VERSION 5.7 ;
  NOWIREEXTENSIONATPIN ON ;
  DIVIDERCHAR "/" ;
  BUSBITCHARS "[]" ;
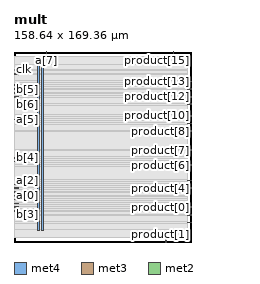
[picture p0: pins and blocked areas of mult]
MACRO mult
  CLASS BLOCK ;
  FOREIGN mult ;
  ORIGIN 0.000 0.000 ;
  SIZE 158.640 BY 169.360 ;
  PIN VGND
    DIRECTION INOUT ;
    USE GROUND ;
    PORT
      LAYER met4 ;
        RECT 24.340 10.640 25.940 158.000 ;
    END
  END VGND
  PIN VPWR
    DIRECTION INOUT ;
    USE POWER ;
    PORT
      LAYER met4 ;
        RECT 21.040 10.640 22.640 158.000 ;
    END
  END VPWR
  PIN a[0]
    DIRECTION INPUT ;
    USE SIGNAL ;
    ANTENNAGATEAREA 0.126000 ;
    PORT
      LAYER met3 ;
        RECT 0.000 40.840 4.000 41.440 ;
    END
  END a[0]
  PIN a[1]
    DIRECTION INPUT ;
    USE SIGNAL ;
    ANTENNAGATEAREA 0.126000 ;
    PORT
      LAYER met3 ;
        RECT 0.000 34.040 4.000 34.640 ;
    END
  END a[1]
  PIN a[2]
    DIRECTION INPUT ;
    USE SIGNAL ;
    ANTENNAGATEAREA 0.126000 ;
    PORT
      LAYER met3 ;
        RECT 0.000 47.640 4.000 48.240 ;
    END
  END a[2]
  PIN a[3]
    DIRECTION INPUT ;
    USE SIGNAL ;
    ANTENNAGATEAREA 0.126000 ;
    PORT
      LAYER met3 ;
        RECT 0.000 51.040 4.000 51.640 ;
    END
  END a[3]
  PIN a[4]
    DIRECTION INPUT ;
    USE SIGNAL ;
    ANTENNAGATEAREA 0.126000 ;
    PORT
      LAYER met3 ;
        RECT 0.000 71.440 4.000 72.040 ;
    END
  END a[4]
  PIN a[5]
    DIRECTION INPUT ;
    USE SIGNAL ;
    ANTENNAGATEAREA 0.126000 ;
    PORT
      LAYER met3 ;
        RECT 0.000 108.840 4.000 109.440 ;
    END
  END a[5]
  PIN a[6]
    DIRECTION INPUT ;
    USE SIGNAL ;
    ANTENNAGATEAREA 0.126000 ;
    PORT
      LAYER met3 ;
        RECT 0.000 132.640 4.000 133.240 ;
    END
  END a[6]
  PIN a[7]
    DIRECTION INPUT ;
    USE SIGNAL ;
    ANTENNAGATEAREA 0.126000 ;
    PORT
      LAYER met2 ;
        RECT 29.070 165.360 29.350 169.360 ;
    END
  END a[7]
  PIN b[0]
    DIRECTION INPUT ;
    USE SIGNAL ;
    ANTENNAGATEAREA 0.126000 ;
    PORT
      LAYER met3 ;
        RECT 0.000 37.440 4.000 38.040 ;
    END
  END b[0]
  PIN b[1]
    DIRECTION INPUT ;
    USE SIGNAL ;
    ANTENNAGATEAREA 0.126000 ;
    PORT
      LAYER met3 ;
        RECT 0.000 27.240 4.000 27.840 ;
    END
  END b[1]
  PIN b[2]
    DIRECTION INPUT ;
    USE SIGNAL ;
    ANTENNAGATEAREA 0.126000 ;
    PORT
      LAYER met3 ;
        RECT 0.000 44.240 4.000 44.840 ;
    END
  END b[2]
  PIN b[3]
    DIRECTION INPUT ;
    USE SIGNAL ;
    ANTENNAGATEAREA 0.126000 ;
    PORT
      LAYER met3 ;
        RECT 0.000 30.640 4.000 31.240 ;
    END
  END b[3]
  PIN b[4]
    DIRECTION INPUT ;
    USE SIGNAL ;
    ANTENNAGATEAREA 0.126000 ;
    PORT
      LAYER met3 ;
        RECT 0.000 74.840 4.000 75.440 ;
    END
  END b[4]
  PIN b[5]
    DIRECTION INPUT ;
    USE SIGNAL ;
    ANTENNAGATEAREA 0.126000 ;
    PORT
      LAYER met3 ;
        RECT 0.000 136.040 4.000 136.640 ;
    END
  END b[5]
  PIN b[6]
    DIRECTION INPUT ;
    USE SIGNAL ;
    ANTENNAGATEAREA 0.126000 ;
    PORT
      LAYER met3 ;
        RECT 0.000 129.240 4.000 129.840 ;
    END
  END b[6]
  PIN b[7]
    DIRECTION INPUT ;
    USE SIGNAL ;
    ANTENNAGATEAREA 0.126000 ;
    PORT
      LAYER met3 ;
        RECT 0.000 139.440 4.000 140.040 ;
    END
  END b[7]
  PIN clk
    DIRECTION INPUT ;
    USE SIGNAL ;
    ANTENNAGATEAREA 0.852000 ;
    PORT
      LAYER met3 ;
        RECT 0.000 153.040 4.000 153.640 ;
    END
  END clk
  PIN product[0]
    DIRECTION OUTPUT ;
    USE SIGNAL ;
    ANTENNADIFFAREA 0.445500 ;
    PORT
      LAYER met3 ;
        RECT 154.640 30.640 158.640 31.240 ;
    END
  END product[0]
  PIN product[10]
    DIRECTION OUTPUT ;
    USE SIGNAL ;
    ANTENNADIFFAREA 0.445500 ;
    PORT
      LAYER met3 ;
        RECT 154.640 112.240 158.640 112.840 ;
    END
  END product[10]
  PIN product[11]
    DIRECTION OUTPUT ;
    USE SIGNAL ;
    ANTENNADIFFAREA 0.445500 ;
    PORT
      LAYER met3 ;
        RECT 154.640 122.440 158.640 123.040 ;
    END
  END product[11]
  PIN product[12]
    DIRECTION OUTPUT ;
    USE SIGNAL ;
    ANTENNADIFFAREA 0.445500 ;
    PORT
      LAYER met3 ;
        RECT 154.640 129.240 158.640 129.840 ;
    END
  END product[12]
  PIN product[13]
    DIRECTION OUTPUT ;
    USE SIGNAL ;
    ANTENNADIFFAREA 0.445500 ;
    PORT
      LAYER met3 ;
        RECT 154.640 136.040 158.640 136.640 ;
    END
  END product[13]
  PIN product[14]
    DIRECTION OUTPUT ;
    USE SIGNAL ;
    ANTENNADIFFAREA 0.445500 ;
    PORT
      LAYER met3 ;
        RECT 154.640 142.840 158.640 143.440 ;
    END
  END product[14]
  PIN product[15]
    DIRECTION OUTPUT ;
    USE SIGNAL ;
    ANTENNADIFFAREA 0.445500 ;
    PORT
      LAYER met2 ;
        RECT 141.770 165.360 142.050 169.360 ;
    END
  END product[15]
  PIN product[1]
    DIRECTION OUTPUT ;
    USE SIGNAL ;
    ANTENNADIFFAREA 0.445500 ;
    PORT
      LAYER met2 ;
        RECT 135.330 0.000 135.610 4.000 ;
    END
  END product[1]
  PIN product[2]
    DIRECTION OUTPUT ;
    USE SIGNAL ;
    ANTENNADIFFAREA 0.445500 ;
    PORT
      LAYER met3 ;
        RECT 154.640 17.040 158.640 17.640 ;
    END
  END product[2]
  PIN product[3]
    DIRECTION OUTPUT ;
    USE SIGNAL ;
    ANTENNADIFFAREA 0.445500 ;
    PORT
      LAYER met3 ;
        RECT 154.640 23.840 158.640 24.440 ;
    END
  END product[3]
  PIN product[4]
    DIRECTION OUTPUT ;
    USE SIGNAL ;
    ANTENNADIFFAREA 0.445500 ;
    PORT
      LAYER met3 ;
        RECT 154.640 47.640 158.640 48.240 ;
    END
  END product[4]
  PIN product[5]
    DIRECTION OUTPUT ;
    USE SIGNAL ;
    ANTENNADIFFAREA 0.445500 ;
    PORT
      LAYER met3 ;
        RECT 154.640 54.440 158.640 55.040 ;
    END
  END product[5]
  PIN product[6]
    DIRECTION OUTPUT ;
    USE SIGNAL ;
    ANTENNADIFFAREA 0.445500 ;
    PORT
      LAYER met3 ;
        RECT 154.640 68.040 158.640 68.640 ;
    END
  END product[6]
  PIN product[7]
    DIRECTION OUTPUT ;
    USE SIGNAL ;
    ANTENNADIFFAREA 0.445500 ;
    PORT
      LAYER met3 ;
        RECT 154.640 81.640 158.640 82.240 ;
    END
  END product[7]
  PIN product[8]
    DIRECTION OUTPUT ;
    USE SIGNAL ;
    ANTENNADIFFAREA 0.445500 ;
    PORT
      LAYER met3 ;
        RECT 154.640 98.640 158.640 99.240 ;
    END
  END product[8]
  PIN product[9]
    DIRECTION OUTPUT ;
    USE SIGNAL ;
    ANTENNADIFFAREA 0.445500 ;
    PORT
      LAYER met3 ;
        RECT 154.640 105.440 158.640 106.040 ;
    END
  END product[9]
  PIN rst
    DIRECTION INPUT ;
    USE SIGNAL ;
    ANTENNAGATEAREA 0.126000 ;
    PORT
      LAYER met3 ;
        RECT 0.000 149.640 4.000 150.240 ;
    END
  END rst
  OBS
      LAYER nwell ;
        RECT 5.330 10.795 152.910 157.845 ;
      LAYER li1 ;
        RECT 5.520 10.795 152.720 157.845 ;
      LAYER met1 ;
        RECT 0.530 10.640 153.020 158.000 ;
      LAYER met2 ;
        RECT 0.550 165.080 28.790 165.360 ;
        RECT 29.630 165.080 141.490 165.360 ;
        RECT 142.330 165.080 151.240 165.360 ;
        RECT 0.550 4.280 151.240 165.080 ;
        RECT 0.550 4.000 135.050 4.280 ;
        RECT 135.890 4.000 151.240 4.280 ;
      LAYER met3 ;
        RECT 0.525 154.040 154.640 157.925 ;
        RECT 4.400 152.640 154.640 154.040 ;
        RECT 0.525 150.640 154.640 152.640 ;
        RECT 4.400 149.240 154.640 150.640 ;
        RECT 0.525 143.840 154.640 149.240 ;
        RECT 0.525 142.440 154.240 143.840 ;
        RECT 0.525 140.440 154.640 142.440 ;
        RECT 4.400 139.040 154.640 140.440 ;
        RECT 0.525 137.040 154.640 139.040 ;
        RECT 4.400 135.640 154.240 137.040 ;
        RECT 0.525 133.640 154.640 135.640 ;
        RECT 4.400 132.240 154.640 133.640 ;
        RECT 0.525 130.240 154.640 132.240 ;
        RECT 4.400 128.840 154.240 130.240 ;
        RECT 0.525 123.440 154.640 128.840 ;
        RECT 0.525 122.040 154.240 123.440 ;
        RECT 0.525 113.240 154.640 122.040 ;
        RECT 0.525 111.840 154.240 113.240 ;
        RECT 0.525 109.840 154.640 111.840 ;
        RECT 4.400 108.440 154.640 109.840 ;
        RECT 0.525 106.440 154.640 108.440 ;
        RECT 0.525 105.040 154.240 106.440 ;
        RECT 0.525 99.640 154.640 105.040 ;
        RECT 0.525 98.240 154.240 99.640 ;
        RECT 0.525 82.640 154.640 98.240 ;
        RECT 0.525 81.240 154.240 82.640 ;
        RECT 0.525 75.840 154.640 81.240 ;
        RECT 4.400 74.440 154.640 75.840 ;
        RECT 0.525 72.440 154.640 74.440 ;
        RECT 4.400 71.040 154.640 72.440 ;
        RECT 0.525 69.040 154.640 71.040 ;
        RECT 0.525 67.640 154.240 69.040 ;
        RECT 0.525 55.440 154.640 67.640 ;
        RECT 0.525 54.040 154.240 55.440 ;
        RECT 0.525 52.040 154.640 54.040 ;
        RECT 4.400 50.640 154.640 52.040 ;
        RECT 0.525 48.640 154.640 50.640 ;
        RECT 4.400 47.240 154.240 48.640 ;
        RECT 0.525 45.240 154.640 47.240 ;
        RECT 4.400 43.840 154.640 45.240 ;
        RECT 0.525 41.840 154.640 43.840 ;
        RECT 4.400 40.440 154.640 41.840 ;
        RECT 0.525 38.440 154.640 40.440 ;
        RECT 4.400 37.040 154.640 38.440 ;
        RECT 0.525 35.040 154.640 37.040 ;
        RECT 4.400 33.640 154.640 35.040 ;
        RECT 0.525 31.640 154.640 33.640 ;
        RECT 4.400 30.240 154.240 31.640 ;
        RECT 0.525 28.240 154.640 30.240 ;
        RECT 4.400 26.840 154.640 28.240 ;
        RECT 0.525 24.840 154.640 26.840 ;
        RECT 0.525 23.440 154.240 24.840 ;
        RECT 0.525 18.040 154.640 23.440 ;
        RECT 0.525 16.640 154.240 18.040 ;
        RECT 0.525 10.715 154.640 16.640 ;
      LAYER met4 ;
        RECT 3.975 148.415 4.305 153.505 ;
  END
END mult
END LIBRARY

